One B-rep face of a CAD part: STEP entity #397.
In plain terms, the spherical face has radius 25.801 mm.
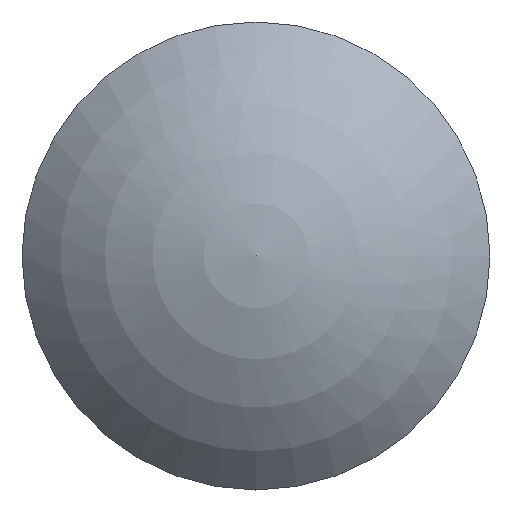
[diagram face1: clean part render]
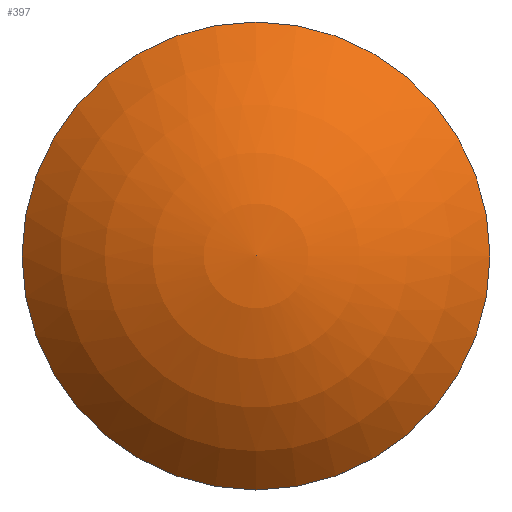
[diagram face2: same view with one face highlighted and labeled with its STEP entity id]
Its self-contained STEP definition (entity closure, numbers rounded to 3 decimals):
#330 = CYLINDRICAL_SURFACE('',#331,19.05);
#331 = AXIS2_PLACEMENT_3D('',#332,#333,#334);
#332 = CARTESIAN_POINT('',(0.,0.,5.8));
#333 = DIRECTION('',(0.,0.,1.));
#334 = DIRECTION('',(1.,0.,-0.));
#348 = VERTEX_POINT('',#349);
#349 = CARTESIAN_POINT('',(19.05,0.,6.6));
#370 = EDGE_CURVE('',#348,#348,#371,.T.);
#371 = SURFACE_CURVE('',#372,(#377,#384),.PCURVE_S1.);
#372 = CIRCLE('',#373,19.05);
#373 = AXIS2_PLACEMENT_3D('',#374,#375,#376);
#374 = CARTESIAN_POINT('',(0.,0.,6.6));
#375 = DIRECTION('',(0.,0.,1.));
#376 = DIRECTION('',(1.,0.,-0.));
#377 = PCURVE('',#330,#378);
#378 = DEFINITIONAL_REPRESENTATION('',(#379),#383);
#379 = LINE('',#380,#381);
#380 = CARTESIAN_POINT('',(0.,0.8));
#381 = VECTOR('',#382,1.);
#382 = DIRECTION('',(1.,0.));
#383 = ( GEOMETRIC_REPRESENTATION_CONTEXT(2) 
PARAMETRIC_REPRESENTATION_CONTEXT() REPRESENTATION_CONTEXT('2D SPACE',''
  ) );
#384 = PCURVE('',#385,#390);
#385 = SPHERICAL_SURFACE('',#386,25.801);
#386 = AXIS2_PLACEMENT_3D('',#387,#388,#389);
#387 = CARTESIAN_POINT('',(0.,0.,-10.801));
#388 = DIRECTION('',(0.,0.,1.));
#389 = DIRECTION('',(1.,0.,-0.));
#390 = DEFINITIONAL_REPRESENTATION('',(#391),#395);
#391 = LINE('',#392,#393);
#392 = CARTESIAN_POINT('',(0.,0.74));
#393 = VECTOR('',#394,1.);
#394 = DIRECTION('',(1.,0.));
#395 = ( GEOMETRIC_REPRESENTATION_CONTEXT(2) 
PARAMETRIC_REPRESENTATION_CONTEXT() REPRESENTATION_CONTEXT('2D SPACE',''
  ) );
#397 = ADVANCED_FACE('',(#398),#385,.T.);
#398 = FACE_BOUND('',#399,.T.);
#399 = EDGE_LOOP('',(#400,#401,#425));
#400 = ORIENTED_EDGE('',*,*,#370,.T.);
#401 = ORIENTED_EDGE('',*,*,#402,.T.);
#402 = EDGE_CURVE('',#348,#403,#405,.T.);
#403 = VERTEX_POINT('',#404);
#404 = CARTESIAN_POINT('',(0.,0.,15.));
#405 = SEAM_CURVE('',#406,(#411,#418),.PCURVE_S1.);
#406 = CIRCLE('',#407,25.801);
#407 = AXIS2_PLACEMENT_3D('',#408,#409,#410);
#408 = CARTESIAN_POINT('',(0.,0.,-10.801));
#409 = DIRECTION('',(0.,-1.,0.));
#410 = DIRECTION('',(0.738,0.,0.674));
#411 = PCURVE('',#385,#412);
#412 = DEFINITIONAL_REPRESENTATION('',(#413),#417);
#413 = LINE('',#414,#415);
#414 = CARTESIAN_POINT('',(0.,0.74));
#415 = VECTOR('',#416,1.);
#416 = DIRECTION('',(0.,1.));
#417 = ( GEOMETRIC_REPRESENTATION_CONTEXT(2) 
PARAMETRIC_REPRESENTATION_CONTEXT() REPRESENTATION_CONTEXT('2D SPACE',''
  ) );
#418 = PCURVE('',#385,#419);
#419 = DEFINITIONAL_REPRESENTATION('',(#420),#424);
#420 = LINE('',#421,#422);
#421 = CARTESIAN_POINT('',(6.283,0.74));
#422 = VECTOR('',#423,1.);
#423 = DIRECTION('',(0.,1.));
#424 = ( GEOMETRIC_REPRESENTATION_CONTEXT(2) 
PARAMETRIC_REPRESENTATION_CONTEXT() REPRESENTATION_CONTEXT('2D SPACE',''
  ) );
#425 = ORIENTED_EDGE('',*,*,#402,.F.);
